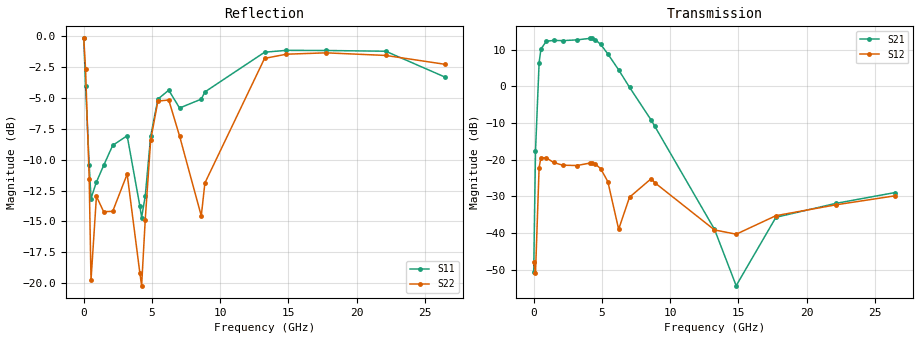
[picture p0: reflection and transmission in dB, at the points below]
!Agilent Technologies,N5242A,MY52422126,A.09.90.01
!Agilent N5242A: A.09.90.01
!Date: Wednesday, November 18, 2015 22:32:31
!Correction: S11(Full 2 Port(1,2))
!S21(Full 2 Port(1,2))
!S12(Full 2 Port(1,2))
!S22(Full 2 Port(1,2))
!S2P File: Measurements: S11, S21, S12, S22:
# Hz S  dB  R 50
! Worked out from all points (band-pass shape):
!   201 points, 10 MHz to 26.5 GHz, reference 50 ohm
!   highest |S21| = 13.04 dB at 4.116 GHz (marker M1); lowest = -54.3 dB at 14.84 GHz (marker M2)
!   |S21| within 3 dB of the highest: 537.1 MHz to 5.203 GHz (4.666 GHz wide, 163 % of centre)
!   lowest |S11| = -14.7 dB at 4.248 GHz (marker M3), VSWR 1.45, Z = 34.5 + j1.31 ohm
!   |S11| at or under -10 dB: 390.7 MHz to 1.658 GHz (1.267 GHz wide, 124 % of centre); 3.689 GHz to 4.733 GHz (1.044 GHz wide, 24.8 % of centre)
!   |S22| runs from -20.2 to -0.2 dB; largest |S21 - S12| = 4.5
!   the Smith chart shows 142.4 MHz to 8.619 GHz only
!   S11 on the Smith chart (normalised r, x): 142.4 MHz: 0.30, -0.51; 407.4 MHz: 0.78, +0.51; 2.129 GHz: 0.50, -0.21; 5.44 GHz: 0.29, +0.10; 7.03 GHz: 1.04, +1.21; 8.619 GHz: 0.94, -1.30
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1e7  -0.20 -11.1  -50.72 -89.4  -47.82 21.6  -0.20 -9.5
1.4245e8  -4.08 -122.2  -17.71 -62.7  -50.97 175.7  -2.71 -99.9
4.0735e8  -10.41 97.0  6.42 -81.4  -22.15 88.1  -11.53 120.6
5.398e8  -13.15 21.7  10.12 -118.6  -19.43 48.3  -19.76 15.2
9.3715e8  -11.81 -93.1  12.26 171.0  -19.51 -17.0  -12.97 -129.8
1.46695e9  -10.47 -128.3  12.48 117.1  -20.76 -57.4  -14.21 -161.0
2.1292e9  -8.85 -148.8  12.42 63.7  -21.50 -94.1  -14.18 -155.9
3.1888e9  -8.07 177.4  12.63 -14.8  -21.59 -148.4  -11.17 175.4
4.11595e9  -13.73 164.1  13.04 -90.5  -20.93 156.2  -19.14 76.1
4.2484e9  -14.68 174.3  13.01 -102.9  -20.93 146.7  -20.19 32.6
4.5133e9  -12.94 -163.6  12.69 -128.6  -21.15 126.2  -14.85 -42.4
4.91065e9  -8.12 -165.6  11.44 -167.2  -22.42 94.2  -8.42 -93.2
5.44045e9  -5.11 167.0  8.81 146.1  -25.95 55.2  -5.27 -137.1
6.23515e9  -4.39 117.1  4.46 84.9  -38.95 42.7  -5.18 174.1
7.02985e9  -5.83 57.3  -0.27 30.3  -30.23 75.0  -8.10 135.2
8.61925e9  -5.11 -58.8  -9.23 -67.7  -25.17 -36.1  -14.55 -26.9
8.88415e9  -4.53 -72.2  -10.92 -83.9  -26.28 -55.9  -11.89 -52.4
1.3255e10  -1.32 -176.9  -38.96 150.4  -39.13 -131.5  -1.82 -175.2
1.48444e10  -1.17 164.3  -54.32 117.0  -40.30 -145.9  -1.48 164.2
1.77583e10  -1.18 137.1  -35.69 177.1  -35.25 179.7  -1.37 135.1
2.212915e10  -1.24 99.2  -31.92 54.6  -32.31 55.3  -1.58 98.6
2.65e10  -3.34 76.0  -28.94 -106.1  -29.83 -97.0  -2.30 72.7
